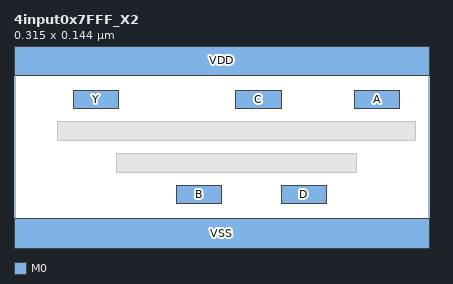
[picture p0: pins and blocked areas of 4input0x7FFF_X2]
MACRO 4input0x7FFF_X2
  CLASS CORE ;
  ORIGIN 0 0 ;
  FOREIGN 4input0x7FFF_X2 0 0 ;
  SIZE 0.3150 BY 0.1440 ;
  SYMMETRY X Y ;
  SITE coresite ;
  PIN A
    DIRECTION INPUT ;
    USE SIGNAL ;
    PORT
      LAYER M0 ;
        RECT 0.2580 0.1010 0.2925 0.1150 ;
    END
  END A
  PIN B
    DIRECTION INPUT ;
    USE SIGNAL ;
    PORT
      LAYER M0 ;
        RECT 0.1230 0.0290 0.1575 0.0430 ;
    END
  END B
  PIN C
    DIRECTION INPUT ;
    USE SIGNAL ;
    PORT
      LAYER M0 ;
        RECT 0.1680 0.1010 0.2025 0.1150 ;
    END
  END C
  PIN D
    DIRECTION INPUT ;
    USE SIGNAL ;
    PORT
      LAYER M0 ;
        RECT 0.2025 0.0290 0.2370 0.0430 ;
    END
  END D
  PIN Y
    DIRECTION OUTPUT ;
    USE SIGNAL ;
    PORT
      LAYER M0 ;
        RECT 0.0450 0.1010 0.0795 0.1150 ;
    END
  END Y
  PIN VDD
    DIRECTION INOUT ;
    USE POWER ;
    SHAPE ABUTMENT ;
    PORT
      LAYER M0 ;
        RECT 0.0000 0.1260 0.3150 0.1620 ;
    END
  END VDD
  PIN VSS
    DIRECTION INOUT ;
    USE GROUND ;
    SHAPE ABUTMENT ;
    PORT
      LAYER M0 ;
        RECT 0.0000 -0.0180 0.3150 0.0180 ;
    END
  END VSS
  OBS
    LAYER M0 ;
      RECT 0.0780 0.0530 0.2595 0.0670 ;
      RECT 0.0330 0.0770 0.3045 0.0910 ;
  END
END 4input0x7FFF_X2
